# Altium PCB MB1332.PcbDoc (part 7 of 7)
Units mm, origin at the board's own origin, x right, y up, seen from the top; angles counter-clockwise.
Board outline 161 x 75 mm, 6 copper layers (Top Layer, Signal Layer 1, Signal Layer 2, Signal Layer 3, Signal Layer 4, Bottom Layer), stack 1.57 mm thick; 387 components, 358 nets, 1659 pads, 1180 vias.

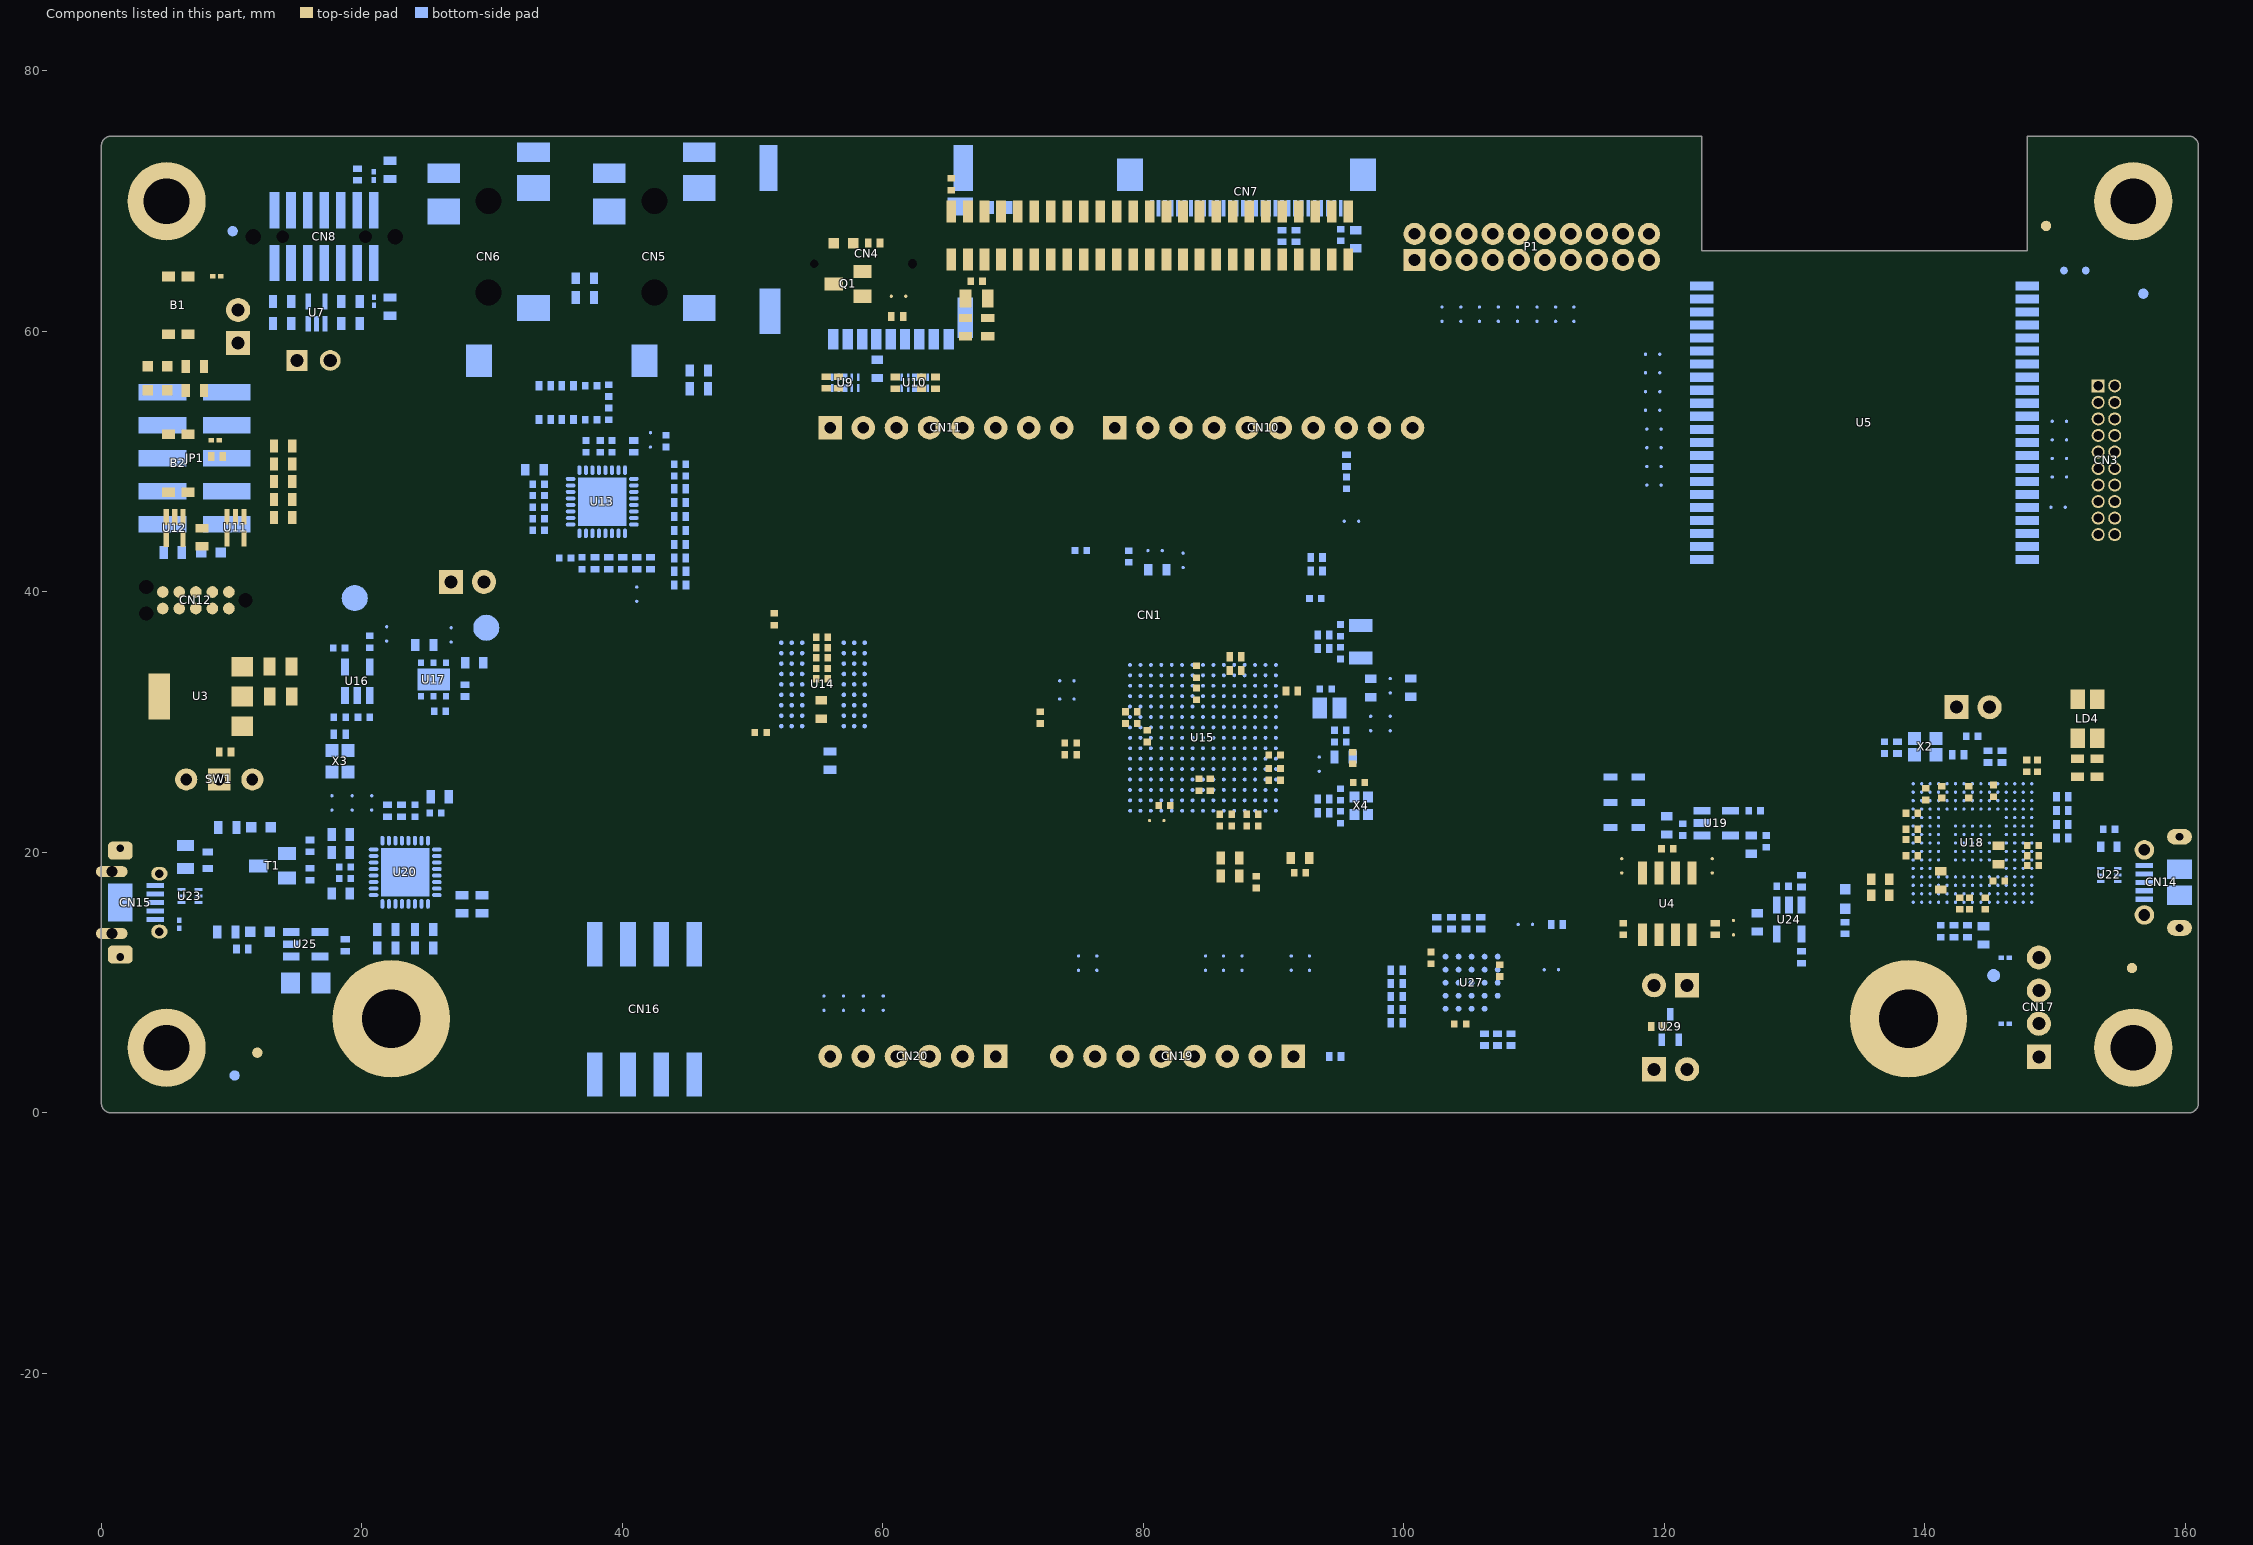
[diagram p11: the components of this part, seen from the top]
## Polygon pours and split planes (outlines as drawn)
GND on Bottom Layer "GND" (solid, remove dead copper, pour order 92): -6.45,72.925 -0.75,78.625 161.225,78.625 166.55,73.3 166.55,1.15 161.375,-4.025 0.525,-4.025 -6.45,2.95
GND on Bottom Layer "GND_L06_P010" (solid, remove dead copper, pour order 10): 96.6,28.248 96.5,28.148 95.3,28.148 95.225,28.223 95.225,29.648 95.35,29.773 96.525,29.773 96.6,29.698
VCAP on Bottom Layer "VCAP_L06_P014" (solid, remove dead copper, pour order 14): 98,29.598 98.1,29.498 98.1,27.123 97.95,26.973 97.075,26.973 96.8,27.248 96.8,29.498 96.9,29.598
VDD_LDO on Bottom Layer "VDD_LDO_L06_P016" (solid, remove dead copper, pour order 16): 99.5,29.598 99.6,29.498 99.6,27.123 99.45,26.973 98.4,26.973 98.3,27.073 98.3,29.498 98.4,29.598
1V8 on Bottom Layer "1V8_L06_P018" (solid, remove dead copper, pour order 18): 101.7,33.098 101.375,32.773 100.15,32.773 99.775,33.148 98.375,33.148 98.225,33.298 98.225,34.098 98.475,34.348 101.55,34.348 101.7,34.198
5V_VIN on Bottom Layer "5V_VIN" (solid, remove dead copper, pour order 90): 116.725,26.1 116.725,25.475 116.457,25.207 113.818,25.207 113.6,25.425 113.6,26.15 113.895,26.445 116.38,26.445
5V_USB_HS on Bottom Layer "5V_USB_HS" (solid, remove dead copper, pour order 88): 7.475,22.525 7.475,20.05 7.275,19.85 5.55,19.85 5.175,20.225 5.175,22.125 5.9,22.85 7.15,22.85
GND on Bottom Layer "GND_L06_P002" (solid, remove dead copper, pour order 2): 99.025,21.123 101.325,21.123 102.325,22.123 102.325,32.298 102.15,32.473 100.1,32.473 100,32.373 100,26.998 99.625,26.623 99.4,26.623 97.425,26.623 97.1,26.298 97.1,25.923 96.725,25.548 95.625,25.548 95.275,25.898 95.275,26.223 95.05,26.448 92.9,26.448 92.725,26.623 92.725,26.948 91.825,27.848 91.3,27.848 90.85,27.398 90.85,26.223 90.875,21.648 91.425,21.098 99,21.098
3V3_SMPS_IN on Bottom Layer "3V3_SMPS_IN_L06_P004" (solid, remove dead copper, pour order 4): 89.975,29.798 94.95,29.798 95.075,29.673 95.075,27.073 95,26.998 92.725,26.998 90.675,29.048 90.275,29.048 89.975,29.348
VDD_SMPS_OUT on Bottom Layer "VDD_SMPS_OUT_L06_P006" (solid, remove dead copper, pour order 6): 94.175,30.148 94.1,30.073 90.05,30.073 89.925,30.198 89.925,30.623 90.05,30.748 90.75,30.748 92.975,32.973 93.825,32.973 93.95,32.848 93.95,32.248 94.175,32.023
3V3_MCU on Bottom Layer "3V3_MCU_L06_P008" (solid, remove dead copper, pour order 8): 95.5,25.973 95.675,25.798 96.45,25.798 96.65,25.998 96.65,27.773 96.55,27.873 95.575,27.873 95.5,27.798
VDD_SMPS_IND_OUT on Bottom Layer "VDD_SMPS_IND_OUT_L06_P012" (solid, remove dead copper, pour order 12): 94.525,30.098 94.4,30.223 94.4,31.923 94.475,31.998 95,31.998 95.475,32.473 99.575,32.473 99.775,32.273 99.775,30.423 99.575,30.223 97.175,30.223 97.05,30.098
GND on Bottom Layer "GND_L06_P020" (solid, remove dead copper, pour order 20): 90.05,30.923 89.9,31.073 89.9,32.473 89.95,32.473 91.675,34.198 91.675,36.823 92.577,37.725 94.102,37.725 95.3,38.923 97.975,38.923 98.625,38.273 98.625,35.773 99.15,35.248 102.025,35.248 102.275,34.998 102.275,34.698 102.15,34.573 98.475,34.573 97.975,34.073 97.975,32.848 97.9,32.773 95,32.773 94.85,32.623 94.85,32.323 94.725,32.198 94.2,32.198 94.125,32.273 94.125,32.848 93.9,33.073 92.825,33.073 91.65,31.898 91.45,31.898 90.475,30.923
NetC93_2 on Bottom Layer "NetC93_2" (solid, remove dead copper, pour order 26): 26.12,36.67 27.392,36.67 27.65,36.412 27.65,35.4 27.275,35.025 26.1,35.025 25.975,34.9 25.975,34.264 25.725,34.014 24.211,34.014 23.925,34.3 23.925,34.85 24.175,35.1 24.632,35.1 24.9,35.368 24.9,36.4 25.175,36.675
NetC112_2 on Bottom Layer "NetC79_2" (solid, remove dead copper, pour order 36): 117.125,26.1 117.375,26.35 118.775,26.35 119.35,25.775 119.35,22.325 119.875,21.8 122.025,21.8 122.175,21.95 122.175,23.775 122.375,23.975 123.625,23.975 124.25,23.35 124.25,21.2 123.725,20.675 117.55,20.675 117.125,21.1
3V3 on Bottom Layer "3V3" (solid, remove dead copper, pour order 86): 27.7,39.05 28.175,38.575 28.175,36.75 27.9,36.475 25.425,36.475 24.7,37.2 24.7,38.7 25.05,39.05
3V3 on Signal Layer 3 "3V3" (solid, remove dead copper, pour order 56): -0.55,75.325 161.125,75.325 162.3,74.15 162.3,-0.4 160.725,-1.975 0.125,-1.975 -1.775,-0.075 -1.775,74.075
VCAP on Signal Layer 3 "VCAP_L04_P022" (solid, remove dead copper, pour order 22): 92.034,26.732 89.113,23.811 85.049,23.811 84.668,24.192 84.668,26.224 84.541,26.351 84.541,26.859 84.668,26.986 84.994,26.986 85.629,26.351 86.057,26.351 86.311,26.605 86.311,28.264 86.065,28.51 86.065,31.431 83.144,31.431 82.636,30.923 82.636,29.018 82.509,28.891 81.62,28.891 81.112,29.399 81.112,33.082 82.255,34.225 86.319,34.225 86.771,33.773 86.827,33.773 86.827,33.466 87.208,33.466 87.208,28.764 97.459,28.764 97.775,28.448 97.775,27.023 97.484,26.732
1V8 on Signal Layer 3 "1V8" (solid, remove dead copper, pour order 50): 40.3,42.525 36.075,42.525 33.6,45.025 26.85,45.025 23.1,41.275 23.1,39.7 23.1,32.625 25.325,30.4 25.325,22.9 24.275,21.85 23.725,21.85 21.725,23.85 21.725,31.725 20.925,32.525 20.925,38.5 20.925,41.85 30.975,51.9 44.4,51.9 45.003,51.297 45.003,47.228
5V on Signal Layer 3 "5V" (solid, remove dead copper, pour order 48): 72,33.075 70.925,32 66.075,32 60.2,37.875 48.125,37.875 41.575,31.325 28.175,31.325 27.725,31.775 27.725,33.875 29.25,35.4 41.425,35.4 47.85,41.825 62,41.825 68.825,35 71.3,35 72,34.3
3V3_MCU on Signal Layer 3 "3V3_MCU_L04_P024" (solid, remove dead copper, pour order 24): 72.75,34.144 71.444,35.45 69.05,35.45 62.165,42.335 47.639,42.335 41.214,35.91 28.815,35.91 28.15,36.575 28.15,41.439 28.961,42.25 30.45,42.25 30.95,41.75 30.95,38.7 31.65,38 39.025,38 46.05,45.025 72.071,45.025 96.075,45.025 97.112,46.062 98.313,46.062 98.475,45.9 98.475,44.7 97.075,43.3 94.55,43.3 94.325,43.025 94.325,39.625 93.27,38.57 81.139,38.57 78.064,35.495 78.064,25.462 78.826,24.7 82.509,24.7 83.017,25.208 83.017,26.07 82.89,26.197 82.89,30.796 83.271,31.177 85.303,31.177 85.321,31.159 85.829,31.159 86.065,30.923 86.065,29.399 85.811,29.145 85.811,28.383 86.065,28.129 86.065,26.732 85.937,26.605 85.544,26.605 85.376,26.773 85.376,27.041 85.176,27.24 84.541,27.24 84.414,27.113 84.414,23.938 84.922,23.43 89.24,23.43 92.158,26.348 96.349,26.348 99.65,26.348 100.05,25.948 100.05,13.948 99.372,13.27 69.682,13.27 69.301,13.651 69.301,29.626 72.75,33.075
VDD_LDO on Signal Layer 3 "VDD_LDO_L04_P028" (solid, remove dead copper, pour order 28): 78.445,25.589 78.953,25.081 82.382,25.081 82.756,25.462 82.756,27.374 80.604,29.526 80.604,33.336 81.874,34.606 86.573,34.606 87.35,33.829 87.35,30.469 87.102,30.467 87.102,29.94 87.97,29.071 97.677,29.071 98.1,28.648 98.1,27.098 98.593,26.605 99.757,26.605 100.05,26.898 100.05,37.448 99.336,38.162 81.239,38.162 78.445,35.368
5V_VIN on Signal Layer 3 "5V_VIN" (solid, remove dead copper, pour order 34): 7.65,27.913 8.962,29.225 13.4,29.225 13.8,29.625 13.8,31.142 13.367,31.575 -0.65,31.575 -1.425,30.75 -1.425,-1.375 -0.975,-1.825 94.95,-1.825 95.875,-0.9 95.875,3.375 95.425,3.825 94.675,3.825 92.9,2.05 20.3,2.05 10.325,12.025 8.75,12.025 7.65,13.125
3V3_STLK on Signal Layer 3 "3V3_STLK" (solid, remove dead copper, pour order 42): 151.175,14.625 151.175,3.225 150.375,2.425 147.35,2.425 146.525,3.25 146.525,14.525 145.75,15.25 135.575,15.25 129.75,21.075 127.25,21.075 126.7,21.625 126.7,25.125 135.925,34.35 152.025,34.35 152.631,33.744 152.631,27.456 150.675,25.5 150.675,22.763 151.007,22.431 154.281,22.431 154.8,22.95 155.8,22.95 156.45,22.3 156.45,19.9
5V on Signal Layer 3 "5V" (solid, remove dead copper, pour order 52): 110.225,70.05 110.85,69.425 110.85,67.625 114.4,64.075 120.767,64.075 121.475,63.367 121.475,20.775 119.825,19.125 117.925,19.125 116.9,20.15 116.9,50.773 104.878,62.9 73.05,62.9 67.375,57.225 62.825,57.225 61.3,58.75 31,58.75 25.125,52.875 4.225,52.875 3.55,52.2 3.625,52.125 3.625,45.275 3.125,44.775 1.345,44.775 0.5,45.62 0.5,55.233 1.192,55.925 24.15,55.925 29.25,61.025 61.875,61.025 70.9,70.05
GND on Signal Layer 2 "GND" (solid, remove dead copper, pour order 82): 1.8,79.7 -1.95,75.95 -1.95,-1.65 1.675,-5.275 162.475,-5.275 166.2,-1.55 166.2,73.375 159.75,79.825 1.925,79.825
5V_VIN on Signal Layer 2 "5V_VIN" (solid, remove dead copper, pour order 60): 115.575,26.35 115.575,25.725 96.2,6.35 96.2,3.95 95.125,2.875 94.4,2.875 93.925,3.35 93.925,4.625 94.95,5.65 94.95,7.475 114.15,26.675 115.25,26.675
5V on Signal Layer 2 "5V" (solid, remove dead copper, pour order 40): 146.2,34.125 133.2,34.125 125.25,26.175 125.25,21.325 123.1,19.175 119.125,19.175 118.275,20.025 118.275,21.4 119.05,22.175 121.1,22.175 122.325,23.4 122.325,27.7 131.25,36.625 145.9,36.625 146.425,37.225 146.425,43.625 147.95,45.15 149.675,45.15 150.075,44.75 150.075,44.025 149.675,43.625 149.15,43.625 148.4,42.875 148.4,36.175 153.25,31.325 153.25,22.275 152.35,21.375 150.775,21.375 150.2,21.95 150.2,30.125
5V on Signal Layer 2 "5V" (solid, remove dead copper, pour order 38): 11.655,31.225 12,30.881 12,30 12.5,29.5 13.275,29.5 13.9,30.125 13.9,30.9 14.225,31.225 25.075,31.225 27.575,33.725 29.125,33.725 29.55,33.3 29.55,30.1 26.15,26.7 5.1,26.7 4.675,26.275 4.675,21.975 10.25,16.4 10.25,13.275 11.3,12.175 13.475,12.175 19,17.7 19,19.075 19.3,19.375 20.35,19.375 20.6,19.125 20.6,16.175 18.587,14.187 18.587,12.838 15.325,9.575 9.966,9.575 6.8,12.775 6.8,13.95 5.825,14.925 5.825,18.6 2.3,22.125 2.3,35.775 0.525,37.55 0.525,55.019 1.406,55.9 2.725,55.9 3.3,55.325 3.3,45.25 5.638,42.913 5.675,32.25 6.7,31.225
5V_VIN on Signal Layer 2 "5V_VIN" (solid, remove dead copper, pour order 64): 6.414,48.314 5.425,47.325 5.425,44.85 8.35,41.925 8.35,35.525 12.15,31.725 12.17,31.725 12.17,30.105 12.6,29.675 13.175,29.675 13.675,30.175 13.675,33.7 10.575,36.8 10.575,46.4 11.15,46.975 12.533,46.975 13.039,47.481 13.039,47.969 12.694,48.314
VIN on Signal Layer 2 "VIN" (solid, remove dead copper, pour order 68): 14.05,35.375 13.6,34.925 12.646,34.925 12.25,35.321 12.25,36.425 13.575,37.75 38.15,37.75 48.85,27.05 48.85,25.575 48.525,25.25 47.075,25.25 36.95,35.375
5V_USB_CHARGER on Signal Layer 2 "5V_USB_CHARGER" (solid, remove dead copper, pour order 70): 155.975,22.175 153,22.175 152.05,21.225 150.4,21.225 150.025,21.6 150.025,25.275 148.9,26.4 134.35,26.4 129.75,21.8 129.75,17.35 126.35,13.95 126.35,12.075 128,10.425 135.1,10.425 138.65,13.975 153.125,13.975 156.35,17.2 156.35,21.8
GND on Top Layer "GND" (solid, remove dead copper, pour order 80): -1.45,78.475 161,78.475 164.75,74.725 164.75,-0.7 162.7,-2.75 1.125,-2.75 -3,1.375 -3,76.925
5V on Top Layer "5V" (solid, remove dead copper, pour order 44): 28.225,33.625 30.225,33.625 30.8,33.05 30.8,24.25 39.85,15.2 39.85,3.25 40.95,2.15 79.85,2.15 80.4,2.7 80.4,5.225 80.775,5.6 82.286,5.6 82.9,4.986 82.9,1.925 81.175,0.2 40,0.2 37.7,2.5 37.7,14.075 27.9,23.875 27.9,33.3
VIN on Top Layer "VIN" (solid, remove dead copper, pour order 66): 75.225,2.925 74.8,2.5 72.45,2.5 71.75,3.2 71.75,13 70.25,14.5 66.25,14.5 63.9,12.15 49.225,12.15 47.425,13.95 47.425,26.9 47.875,27.35 49.375,27.35 50.075,26.65 50.075,16.15 52.375,13.85 61.05,13.85 62.6,15.4 74.475,15.4 75.225,14.65
E5V on Top Layer "E5V" (solid, remove dead copper, pour order 58): 12.25,55.825 12.25,54 12.8,53.45 12.8,52.55 12.525,52.275 11.4,52.275 10.5,53.175 10.5,54.3 8.725,56.075 8.725,57.229 8.725,60.358 8.967,60.6 11.65,60.6 12.25,60 12.25,57.15
GND on Signal Layer 4 "GND" (solid, remove dead copper, pour order 78): -2.9,74.65 -2.9,0.825 -0.1,-1.975 0.025,-1.85 162.65,-1.85 165.45,0.95 165.45,72.875 161.125,77.2 -0.35,77.2
5V_USB_HS on Signal Layer 4 "5V_USB_HS" (solid, remove dead copper, pour order 72): -0.7,22.8 17.275,22.8 36.025,4.05 112.85,4.05 113.875,5.075 113.875,22 114.35,22.475 115.775,22.475 116.85,21.4 116.85,-1.025 115.85,-2.025 -1.125,-2.025 -2.725,-0.425 -1.3,1 -1.3,22.2
5V_USB_CHARGER on Signal Layer 4 "5V_USB_CHARGER" (solid, remove dead copper, pour order 74): 1.725,45.6 12.65,45.6 15.1,43.15 15.1,37.75 44.575,8.275 108.275,8.275 110.05,10.05 110.05,22.325 112.6,24.875 126.7,24.875 131.4,20.175 131.4,18.75 130.975,18.325 129.825,18.325 126.75,21.4 117,21.4 115.85,22.55 114.25,22.55 113.725,22.025 113.725,5.075 112.99,4.34 35.91,4.34 17.25,23 -0.55,23 -0.55,23.025 -1.125,23.6 -1.125,42.75
5V_USB_STLK on Signal Layer 4 "5V_USB_STLK" (solid, remove dead copper, pour order 76): -0.05,56.675 13.725,56.675 19.7,50.7 19.7,42.35 48.575,13.475 104.675,13.475 105.825,14.625 105.825,25.35 110.525,30.05 133.325,30.05 137.1,26.275 137.1,-2.125 0.65,-2.125 -1.475,0 -1.225,0.25 -1.225,55.5
GND on Signal Layer 1 "GND_L02_P000" (solid, remove dead copper, pour order 0): 161,75 161,0 0,0 0,75

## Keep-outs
Keep-Out Layer:
  region: 158.675,28.325 158.675,36.825 156.7,36.825 156.7,28.325

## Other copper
Top Layer:
  text "1" at 158.272,28.618 h2 r90
  text ".Layer_Name" at 39.428,-21.858 h3
  text ".GTL" at 81.123,-21.858 h3
Signal Layer 1:
  text "2" at 158.272,29.868 h2 r90
  text ".Layer_Name" at 39.428,-21.858 h3
  text ".G1" at 81.123,-21.858 h3
Signal Layer 2:
  text "3" at 158.272,31.368 h2 r90
  text ".Layer_Name" at 39.428,-21.858 h3
  text ".G2" at 81.123,-21.858 h3
Signal Layer 3:
  text "4" at 158.272,33.618 h2 r90
  text ".Layer_Name" at 39.46,-21.841 h3
  text ".G3" at 81.155,-21.841 h3
Signal Layer 4:
  text "5" at 158.272,35.118 h2 r90
  text ".Layer_Name" at 39.46,-21.841 h3
  text ".G4" at 81.155,-21.841 h3
Bottom Layer:
  text "6" at 158.272,36.618 h2 r90
  text ".GBL" at 69.92,-21.89 h3
  text ".Layer_Name" at 111.234,-21.89 h3

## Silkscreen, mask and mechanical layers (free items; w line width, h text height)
Top Overlay:
  lines w0.1: 6.6,23.5 12.775,23.5 ; 0.35,21.8 0.35,27.475 2.3,27.475 2.3,21.8 0.35,21.8 ; 159.025,22.15 159.025,30.375 160.65,30.375 160.65,22.15 159.025,22.15
  lines w0.254: 102.05,61.725 102.05,63.925 110.45,63.925 110.45,61.7 102.075,61.7 ; 156.2,27.325 156.225,27.35 ; 1.3,60 2.85,60 2.85,64.775 1.3,64.775 1.3,60 ; 1.55,48.15 1.55,51.8 3.1,51.8 3.1,48.15 1.55,48.15 ; 14.016,37.525 16.016,37.525 16.016,41.775 14.016,41.775 14.016,37.525
  text "RGB LCD" at 83,71.5 h2
  text "STMOD+" at 102.65,62.125 h2
  text "RESET" at 2.55,60.45 h1.3 r90
  text "USER" at 2.7,48.425 h1.3 r90
  text "TAG" at 15.591,37.775 h2 r90
  text "USB STLINK" at 160.3,22.475 h1.5 r90
  text "OTG HS" at 1.8,22.2 h1.5 r90
  text "0 / FLASH" at 11.25,21.825 h1.5
  text "1 / SYS  / MEM" at 4.25,20.725 h1.5
  text "J" at 6.075,13.675 h15
  text "MB1332C" at 4.275,10.375 h3
  text ".Layer_Name" at 39.428,-21.858 h3
  text ".GTO" at 81.123,-21.858 h3
Bottom Overlay:
  lines w0.01: 15.95,55.3 15.95,55.3
  lines w0.1: 15.05,56.1 16.225,54.925 ; 17.575,56.1 18.75,54.925 ; 0.9,21.375 0.9,27.05 2.8,27.05 2.8,21.375 0.9,21.375 ; 159.075,22.4 160.575,22.4 160.575,30.5 159.075,30.5 159.075,22.4
  lines w0.254: 71.9,71.075 71.925,71.1 ; 73.325,71.425 69.05,71.425 69.05,73.925 73.35,73.925 73.35,71.45 ; 84.475,65.875 76.075,65.875 76.075,68.125 84.475,68.125 84.475,66.225 ; 88.175,65.625 88.175,65.975 ; 127.675,30.4 122.8,30.4 122.8,32.65 127.7,32.65 127.7,30.425 ; 128.525,31.95 128.55,31.975 ; 0.35,45.175 2.475,45.175 2.475,55.25 0.35,55.25 0.35,45.175 ; 9.475,72.075 9.475,74.2 16.725,74.2 16.725,72.075 9.475,72.075 ; 28.75,2 28.75,4.375 35.5,4.375 35.5,4.125 35.5,2 28.75,2 ; 34.925,67.1 34.925,74.35 37.3,74.35 37.3,67.1 34.925,67.1 ; 47.625,65.475 49.875,65.475 49.875,74.25 47.625,74.25 47.625,65.475 ; 51.75,38.25 51.75,40.75 59,40.75 59,38.25 51.75,38.25 ; 92.35,13.825 92.35,16.25 101,16.25 101,13.825 92.35,13.825 ; 123.75,2.15 123.75,4.475 131,4.475 131,2.15 123.75,2.15
  text "DEBUG" at 16.25,72.475 h2
  text "µSD" at 72.775,72.225 h2
  text "AUDIO IN" at 35.65,67.95 h1.5 r270
  text "CAMERA" at 84.175,66.35 h2
  text "AUDIO OUT" at 48.2,66.2 h1.5 r270
  text "STLK" at 14.6,54.45 h1.3
  text "E5V" at 13.95,52.325 h1.3
  text "JTCK" at 18.475,51.975 h1.5 r315
  text "JTMS" at 21,51.95 h1.5 r315
  text "U5V" at 13.95,49.775 h1.3
  text "D7" at 74.1,49.65 h1.3 r315
  text "D0" at 56.375,49.6 h1.3 r315
  text "D4" at 66.375,49.575 h1.3 r315
  text "D6" at 71.5,49.575 h1.3 r315
  text "D5" at 68.975,49.55 h1.3 r315
  text "D9" at 80.575,49.55 h1.3 r315
  text "D1" at 58.875,49.5 h1.3 r315
  text "D3" at 63.9,49.5 h1.3 r315
  text "D8" at 77.95,49.5 h1.3 r315
  text "D2" at 61.35,49.475 h1.3 r315
  text "D10" at 83.6,49.225 h1.3 r315
  text "D11" at 86.125,49.225 h1.3 r315
  text "D14" at 99.275,49.125 h1.3 r315
  text "D12" at 88.475,49.1 h1.3 r315
  text "D15" at 101.9,49.075 h1.3 r315
  text "D13" at 91.225,49.025 h1.3 r315
  text "GND" at 93.575,48.9 h1.3 r315
  text "AVDD" at 98,48.45 h1.3 r315
  text "ARD" at 14.25,47.225 h1.3
  text "5V POWER" at 0.85,45.575 h2 r270
  text "CHGR" at 15.25,44.725 h1.3
  text "SDRAM" at 58.5,38.85 h2
  text "H" at 115.95,38.075 h20
  text "G" at 70.4,34.525 h12
  text "NRST" at 145.375,32.75 h1.5
  text "WIFI" at 126.975,30.925 h2
  text "C" at 115.1,30.8 h15
  text "F" at 70,25.65 h15
  text "J" at 44.65,22.75 h15
  text "USB STLINK" at 159.35,22.575 h1.5 r270
  text "OTG HS" at 1.325,21.725 h1.5 r270
  text "MB1332C" at 46.05,19.275 h3
  text "I" at 69.625,16.25 h15
  text "E" at 59.825,16.15 h15
  text "OCTOSPI" at 100.55,14.275 h2
  text "SWDIO" at 153.6,14.1 h1.3 r45
  text "GND" at 152.6,10.6 h1.3 r45
  text "SWCLK" at 153.625,8.875 h1.3 r45
  text "+3V3" at 152.625,5.425 h1.3 r45
  text "FDCAN" at 130.05,2.65 h2
  text "Ext I2C" at 35.225,2.45 h2
  text "A3" at 61.45,1.3 h1.3 r315
  text "A5" at 56.175,1.275 h1.3 r315
  text "A4" at 58.925,1.275 h1.3 r315
  text "A0" at 69.35,1.225 h1.3 r315
  text "A1" at 66.55,1.2 h1.3 r315
  text "A2" at 64.125,1.15 h1.3 r315
  text "5V" at 81.75,1.125 h1.3 r315
  text "3V3" at 84.5,0.875 h1.3 r315
  text "VIN" at 74.225,0.775 h1.3 r315
  text "GND" at 77.325,0.525 h1.3 r315
  text "GND" at 79.95,0.5 h1.3 r315
  text "NRST" at 87.9,0.1 h1.3 r315
  text "IOREF" at 90.975,0.1 h1.3 r315
  text ".GBO" at 69.92,-21.89 h3
  text ".Layer_Name" at 111.234,-21.89 h3
Top Paste:
  text ".Layer_Name" at 39.401,-21.848 h3
  text ".GTP" at 81.096,-21.848 h3
Bottom Paste:
  text ".GBP" at 69.811,-21.875 h3
  text ".Layer_Name" at 111.125,-21.875 h3
Top Solder:
  region: 158.675,28.325 158.675,36.825 156.7,36.825 156.7,28.325
  text ".Layer_Name" at 39.426,-21.923 h3
  text ".GTS" at 81.121,-21.923 h3
Bottom Solder:
  region: 158.675,28.325 158.675,36.825 156.675,36.825 156.675,28.325
  text ".GBS" at 69.836,-21.95 h3
  text ".Layer_Name" at 111.15,-21.95 h3
M1-Board Shape:
  lines w0.1: 0,0.75 ccw(c0.75,0.75) 0.75,0 160.25,0 ccw(c160.25,0.75) 161,0.75 161,74.25 ccw(c160.25,74.25) 160.25,75 158.076,75 147.861,75 147.861,66.2 122.861,66.2 122.861,75 119.525,75 40.625,75 0.75,75 ccw(c0.75,74.25) 0,74.25 0,0.75
M2-Board Dimensions:
  text ".Layer_Name" at 39.428,-21.858 h3
  text ".GM2" at 81.123,-21.858 h3
M14-Top Assembly:
  text ".Layer_Name" at 39.428,-21.858 h3
  text ".GM14" at 81.123,-21.858 h3
M15-Bottom Assembly:
  text ".GM15" at 69.92,-21.89 h3
  text ".Layer_Name" at 111.234,-21.89 h3
Drill Drawing:
  drawing of 454 lines, arcs and shapes, not listed
  text "IMPEDANCE TABLE : SDRAM, SD CARD, ULPI, CAMERA" at 187.175,131.866 h3
  text "PCB SPECIFICATIONS :" at 1.4,131.279 h3
  text "PCB : TYPE 3" at 149.812,131.047 h3
  text "A.   MATERIAL :" at 1.4,127.279 h3
  text "FR-4" at 39.9,127.279 h3
  text "TG-170" at 56.4,127.279 h3
  text "X  TG-150" at 74.65,127.279 h3
  text "TG-140" at 90.65,127.279 h3
  text "LAYER" at 191.425,126.866 h3
  text "TRACE" at 207.675,126.866 h3
  text "SPACING" at 218.175,126.866 h3
  text "IMPEDANCE" at 231.675,126.866 h3
  text "IMPEDANCE" at 248.675,126.866 h3
  text "TOL." at 267.425,126.866 h3
  text "ASPECT-RATIO, AXE Z :" at 149.812,125.547 h3
  text "(mm)" at 221.5,124.391 h2.5
  text "(mm)" at 209.675,124.341 h2.5
  text "B.   MATERIAL FAMILY :" at 1.4,124.279 h3
  text "N/A" at 39.9,124.279 h3
  text "(Single ended)" at 232.175,124.116 h2.5
  text "(Differential)" at 249.925,124.116 h2.5
  text "C.   SOLDERMASK COLOR :" at 1.4,121.279 h3
  text "GREEN" at 39.9,121.279 h3
  text "WHITE" at 56.4,121.279 h3
  text "X  BLUE" at 74.65,121.279 h3
  text "BLACK" at 90.65,121.279 h3
  text "+/- 15%" at 266.48,120.476 h3
  text "0.127" at 208.65,120.391 h3
  text "n/a" at 220.675,120.366 h3
  text "TOP/BOTTOM" at 187.655,120.351 h3
  text "55 ohm" at 235.03,120.301 h3
  text "n/a" at 254.58,120.251 h3
  text "6:1 to 8:1 / LEVEL \"B\"" at 149.83,118.799 h3
  text "D.   SILKSCREEN COLOR :" at 1.4,118.279 h3
  text "X  WHITE" at 39.9,118.279 h3
  text "YELLOW" at 56.4,118.279 h3
  text "BLACK" at 74.65,118.279 h3
  text "Blue ink PANTONE 2955" at 90.65,118.279 h3
  text "+/- 15%" at 266.485,116.961 h3
  text "0.102" at 208.655,116.876 h3
  text "n/a" at 220.68,116.851 h3
  text "LAYER 3" at 189.6,116.816 h3
  text "55 ohm" at 235.035,116.786 h3
  text "n/a" at 254.585,116.736 h3
  text "E.   SURFACE FINISH :" at 1.4,115.279 h3
  text "X  ENIG" at 39.9,115.279 h3
  text "IMMERSION SILVER" at 56.4,115.279 h3
  text "IMMERSION TIN" at 90.65,115.279 h3
  text "MINIMUM PARAMETERS" at 149.857,113.198 h3
  text "HASL" at 39.9,112.279 h3
  text "HASL (PB-FREE)" at 56.4,112.279 h3
  text "GOLDEN FINGER" at 90.65,112.279 h3
  text "IMPEDANCE TABLE   USB OTG HS, USB HS STLINK V3E" at 187.05,111.69 h3
  text "F.   IMPEDANCE CONTROL :" at 1.4,109.279 h3
  text "NO" at 39.9,109.279 h3
  text "X  YES  (SEE IMPEDANCE TABLE FOR DETAIL INFORMATION)" at 56.4,109.279 h3
  text "DEFAULT" at 149.857,107.698 h3
  text "LAYER" at 191.3,106.69 h3
  text "TRACE" at 207.55,106.69 h3
  text "SPACING" at 218.05,106.69 h3
  text "IMPEDANCE" at 231.55,106.69 h3
  text "IMPEDANCE" at 248.55,106.69 h3
  text "TOL." at 267.3,106.69 h3
  text "G.   THROUGH VIA :" at 1.4,106.279 h3
  text "PLUG THE VIAS WHICH ARE COVERED WITH SOLDERMASK ONE OR TWO SIDE." at 39.9,106.279 h3
  text "(mm)" at 221.375,104.215 h2.5
  text "(mm)" at 209.55,104.165 h2.5
  text "(Single ended)" at 232.05,103.94 h2.5
  text "(Differential)" at 249.8,103.94 h2.5
  text "PLUG MATERIAL :" at 39.9,103.279 h3
  text "X  SOLDERMASK" at 65.4,103.279 h3
  text "NON-CONDUCTIVE EPOXY." at 90.65,103.279 h3
  text "TRACKS : 0.1mm           / GAPS : 0.1mm" at 149.857,101.948 h3
  text "+/- 15%" at 266.355,100.3 h3
  text "H.   STACK-UP :" at 1.4,100.279 h3
  text "SEE LAYER STACK-UP SEQUENCE FOR OVERALL THICKNESS." at 39.9,100.279 h3
  text "0.155" at 208.525,100.215 h3
  text "0.226" at 220.55,100.19 h3
  text "TOP/BOTTOM" at 187.53,100.175 h3
  text "n/a" at 234.905,100.125 h3
  text "90 ohm" at 250.991,99.949 h3
  text "+/- 15%" at 266.36,96.785 h3
  text "0.130" at 208.53,96.7 h3
  text "0.251" at 220.555,96.675 h3
  text "LAYER 3" at 189.475,96.64 h3
  text "90 ohm" at 250.991,96.647 h3
  text "n/a" at 234.91,96.61 h3
  text "Layer" at 188.2,90.225 h2
  text "Name" at 196.574,90.225 h2
  text "Material" at 212.771,90.225 h2
  text "Thickness" at 227.325,90.225 h2
  text "Constant" at 239.28,90.225 h2
  text "Board Layer Stack" at 250.344,90.225 h2
  text "1" at 188.2,86.225 h2
  text "Top Overlay" at 196.574,86.225 h2
  text "2" at 188.2,82.225 h2
  text "Top Solder" at 196.574,82.225 h2
  text "Solder Resist" at 212.771,82.225 h2
  text "0,015mm" at 227.325,82.225 h2
  text "3,5" at 239.28,82.225 h2
  text "3" at 188.2,78.225 h2
  text "Top Layer" at 196.574,78.225 h2
  text "Copper" at 212.771,78.225 h2
  text "0,042mm" at 227.325,78.225 h2
  text "4" at 188.2,74.225 h2
  text "Dielectric 1" at 196.574,74.225 h2
  text "FR-4" at 212.771,74.225 h2
  text "0,099mm" at 227.325,74.225 h2
  text "4,2" at 239.28,74.225 h2
  text "5" at 188.2,70.225 h2
  text "Signal Layer 1" at 196.574,70.225 h2
  text "Copper" at 212.771,70.225 h2
  text "0,035mm" at 227.325,70.225 h2
  text "6" at 188.2,66.225 h2
  text "Dielectric 2" at 196.574,66.225 h2
  text "0,102mm" at 227.325,66.225 h2
  text "4,2" at 239.28,66.225 h2
  text "7" at 188.2,62.225 h2
  text "Signal Layer 2" at 196.574,62.225 h2
  text "Copper" at 212.771,62.225 h2
  text "0,035mm" at 227.325,62.225 h2
  text "8" at 188.2,58.225 h2
  text "Dielectric 3" at 196.574,58.225 h2
  text "0,946mm" at 227.325,58.225 h2
  text "4,2" at 239.28,58.225 h2
  text "9" at 188.2,54.225 h2
  text "Signal Layer 3" at 196.574,54.225 h2
  text "Copper" at 212.771,54.225 h2
  text "0,035mm" at 227.325,54.225 h2
  text "10" at 188.2,50.225 h2
  text "Dielectric 4" at 196.574,50.225 h2
  text "0,102mm" at 227.325,50.225 h2
  text "4,2" at 239.28,50.225 h2
  text "11" at 188.2,46.225 h2
  text "Signal Layer 4" at 196.574,46.225 h2
  text "Copper" at 212.771,46.225 h2
  text "0,035mm" at 227.325,46.225 h2
  text "12" at 188.2,42.225 h2
  text "Dielectric 5" at 196.574,42.225 h2
  text "0,099mm" at 227.325,42.225 h2
  text "4,2" at 239.28,42.225 h2
  text "13" at 188.2,38.225 h2
  text "Bottom Layer" at 196.574,38.225 h2
  text "Copper" at 212.771,38.225 h2
  text "0,042mm" at 227.325,38.225 h2
  text "14" at 188.2,34.225 h2
  text "Bottom Solder" at 196.574,34.225 h2
  text "Solder Resist" at 212.771,34.225 h2
  text "0,015mm" at 227.325,34.225 h2
  text "3,5" at 239.28,34.225 h2
  text "15" at 188.2,30.225 h2
  text "Bottom Overlay" at 196.574,30.225 h2
  text "Symbol" at 188.595,24.234 h2.4
  text "Count" at 197.994,24.234 h2.4
  text "Hole Size" at 208.625,24.234 h2.4
  text "Plated" at 227.952,24.234 h2.4
  text "Hole Type" at 236.203,24.234 h2.4
  text "Drill Layer Pair" at 248.214,24.234 h2.4
  text "Hole Length" at 270.995,24.234 h2.4
  text "Routed Path Length" at 289.294,24.234 h2.4
  text "1180" at 197.994,20.09 h2
  text "0,200mm (7,87mil)" at 208.625,20.09 h2
  text "PTH" at 227.952,20.09 h2
  text "Round" at 236.203,20.09 h2
  text "Top Layer - Bottom Layer" at 248.214,20.09 h2
  text "-" at 270.995,20.09 h2
  text "-" at 289.294,20.09 h2
  text "4" at 197.994,15.947 h2
  text "0,600mm (23,62mil)" at 208.625,15.947 h2
  text "PTH" at 227.952,15.947 h2
  text "Slot" at 236.203,15.947 h2
  text "Top Layer - Bottom Layer" at 248.214,15.947 h2
  text "1,300mm (51,18mil)" at 270.995,15.947 h2
  text "0,700mm (27,56mil)" at 289.294,15.947 h2
  text "T" at 187.807,15.694 h1.84
  text "2" at 197.994,11.804 h2
  text "0,650mm (25,59mil)" at 208.625,11.804 h2
  text "PTH" at 227.952,11.804 h2
  text "Slot" at 236.203,11.804 h2
  text "Top Layer - Bottom Layer" at 248.214,11.804 h2
  text "0,850mm (33,47mil)" at 270.995,11.804 h2
  text "0,200mm (7,88mil)" at 289.294,11.804 h2
  text "V" at 187.807,11.551 h1.84
  text "1" at 197.994,7.661 h2
  text "0,650mm (25,59mil)" at 208.625,7.661 h2
  text "NPTH" at 227.952,7.661 h2
  text "Round" at 236.203,7.661 h2
  text "Top Layer - Bottom Layer" at 248.214,7.661 h2
  text "-" at 270.995,7.661 h2
  text "-" at 289.294,7.661 h2
  text "R" at 187.807,7.407 h1.84
  text "1" at 197.994,3.518 h2
  text "0,700mm (27,56mil)" at 208.625,3.518 h2
  text "NPTH" at 227.952,3.518 h2
  text "Round" at 236.203,3.518 h2
  text "Top Layer - Bottom Layer" at 248.214,3.518 h2
  text "-" at 270.995,3.518 h2
  text "-" at 289.294,3.518 h2
  text "S" at 187.807,3.264 h1.84
  text "20" at 197.994,-0.625 h2
  text "0,700mm (27,56mil)" at 208.625,-0.625 h2
  text "PTH" at 227.952,-0.625 h2
  text "Round" at 236.203,-0.625 h2
  text "Top Layer - Bottom Layer" at 248.214,-0.625 h2
  text "-" at 270.995,-0.625 h2
  text "-" at 289.294,-0.625 h2
  text "Q" at 187.807,-0.879 h1.84
  text "2" at 197.994,-4.768 h2
  text "0,850mm (33,47mil)" at 208.625,-4.768 h2
  text "NPTH" at 227.952,-4.768 h2
  text "Slot" at 236.203,-4.768 h2
  text "Top Layer - Bottom Layer" at 248.214,-4.768 h2
  text "2,425mm (95,47mil)" at 270.995,-4.768 h2
  text "1,575mm (62,01mil)" at 289.294,-4.768 h2
  text "U" at 187.807,-5.022 h1.84
  text "57" at 197.994,-8.911 h2
  text "0,900mm (35,43mil)" at 208.625,-8.911 h2
  text "PTH" at 227.952,-8.911 h2
  text "Round" at 236.203,-8.911 h2
  text "Top Layer - Bottom Layer" at 248.214,-8.911 h2
  text "-" at 270.995,-8.911 h2
  text "-" at 289.294,-8.911 h2
  text "K" at 187.807,-9.165 h1.84
  text "2" at 197.994,-13.054 h2
  text "0,970mm (38,19mil)" at 208.625,-13.054 h2
  text "NPTH" at 227.952,-13.054 h2
  text "Round" at 236.203,-13.054 h2
  text "Top Layer - Bottom Layer" at 248.214,-13.054 h2
  text "-" at 270.995,-13.054 h2
  text "-" at 289.294,-13.054 h2
  text "16" at 197.994,-17.197 h2
  text "1,000mm (39,37mil)" at 208.625,-17.197 h2
  text "PTH" at 227.952,-17.197 h2
  text "Round" at 236.203,-17.197 h2
  text "Top Layer - Bottom Layer" at 248.214,-17.197 h2
  text "-" at 270.995,-17.197 h2
  text "-" at 289.294,-17.197 h2
  text "N" at 187.807,-17.451 h1.84
  text "3" at 197.994,-21.34 h2
  text "1,100mm (43,31mil)" at 208.625,-21.34 h2
  text "NPTH" at 227.952,-21.34 h2
  text "Round" at 236.203,-21.34 h2
  text "Top Layer - Bottom Layer" at 248.214,-21.34 h2
  text "-" at 270.995,-21.34 h2
  text "-" at 289.294,-21.34 h2
  text "O" at 187.807,-21.594 h1.84
  text ".Layer_Name" at 39.428,-21.858 h3
  text ".DRL" at 81.123,-21.858 h3
  text "2" at 197.994,-25.484 h2
  text "1,190mm (46,85mil)" at 208.625,-25.484 h2
  text "NPTH" at 227.952,-25.484 h2
  text "Round" at 236.203,-25.484 h2
  text "Top Layer - Bottom Layer" at 248.214,-25.484 h2
  text "-" at 270.995,-25.484 h2
  text "-" at 289.294,-25.484 h2
  text "4" at 197.994,-29.627 h2
  text "2,000mm (78,74mil)" at 208.625,-29.627 h2
  text "NPTH" at 227.952,-29.627 h2
  text "Round" at 236.203,-29.627 h2
  text "Top Layer - Bottom Layer" at 248.214,-29.627 h2
  text "-" at 270.995,-29.627 h2
  text "-" at 289.294,-29.627 h2
  text "M" at 187.807,-29.88 h1.84
  text "4" at 197.994,-33.77 h2
  text "3,500mm (137,80mil)" at 208.625,-33.77 h2
  text "PTH" at 227.952,-33.77 h2
  text "Round" at 236.203,-33.77 h2
  text "Top Layer - Bottom Layer" at 248.214,-33.77 h2
  text "-" at 270.995,-33.77 h2
  text "-" at 289.294,-33.77 h2
  text "P" at 187.807,-34.023 h1.84
  text "2" at 197.994,-37.913 h2
  text "4,500mm (177,17mil)" at 208.625,-37.913 h2
  text "PTH" at 227.952,-37.913 h2
  text "Round" at 236.203,-37.913 h2
  text "Top Layer - Bottom Layer" at 248.214,-37.913 h2
  text "-" at 270.995,-37.913 h2
  text "-" at 289.294,-37.913 h2
  text "1300 Total" at 197.994,-42.056 h2
  text "Slot definitions :" at 188.595,-44.956 h2
  text "Routed Path Length" at 202.248,-44.956 h2
  text "= Calculated from tool start centre position to tool end centre position." at 219.161,-44.956 h2
  text "Hole Length" at 202.248,-46.613 h2
  text "= Routed Path Length + Tool Size = Slot length as defined in the PCB layout" at 212.882,-46.613 h2
M20-Top Title Box:
  circle w0.254: c117.433,-28.579 r1.3
  region: 102.955,-29.672 92.199,-29.672 93.192,-27.179 101.05,-27.179 101.498,-26.42 103.707,-28.968
  region: 116.958,-21.342 101.431,-21.342 100.736,-23.118 99.526,-24.343 98.129,-22.483 98.129,-20.832 99.272,-19.435 100.708,-19.056 116.958,-19.056
  lines w0.254: 93.192,-27.179 101.984,-27.179 98.918,-23.641 cw(c100.721,-21.697) 100.962,-19.056 117.726,-19.056 116.964,-21.342 ; 96.506,-18.809 cw(c98.932,-19.78) 99.168,-17.177 ; 96.545,-18.777 92.199,-29.672 111.521,-29.672 ccw(c111.77,-26.937) 114.319,-27.957 ; 98.285,-22.711 103.707,-28.968 ; 98.539,-22.711 103.844,-28.833 ; 98.539,-22.457 103.844,-28.579 ; 98.637,-21.342 111.63,-21.342 ; 98.666,-22.33 103.971,-28.452 ; 98.793,-22.203 104.098,-28.325 ; 98.92,-22.076 104.225,-28.198 ; 99.047,-21.949 104.352,-28.071 ; 99.101,-19.997 104.406,-26.118 ; 99.17,-17.177 118.619,-17.177 114.32,-27.955 ; 99.174,-21.822 104.424,-27.881 ; 99.174,-21.568 104.479,-27.69 ; 99.174,-21.314 104.479,-27.436 ; 99.174,-20.425 104.479,-26.547 ; 99.301,-21.187 104.606,-27.309 ; 99.301,-20.806 104.606,-26.928 ; 100.672,-27.192 ccw(c100.777,-26.657) 101.075,-26.2 ; 101.759,-21.329 ccw(c101.733,-21.896) 101.403,-22.358 103.767,-25.087 cw(c101.964,-27.031) 102.696,-29.579 ; 108.04,-29.468 110.929,-21.088 ; 108.262,-29.418 111.132,-21.097 ; 108.389,-29.418 111.259,-21.097 ; 108.643,-29.418 111.513,-21.097 ; 108.897,-29.418 111.767,-21.097 ; 109.151,-29.418 112.021,-21.097 ; 109.405,-29.418 112.275,-21.097 ; 109.659,-29.418 112.529,-21.097 ; 109.913,-29.418 112.783,-21.097 ; 110.167,-29.418 113.037,-21.097 ; 110.376,-29.468 113.265,-21.088 ; 113.265,-21.342 116.958,-21.342 ; 116.29,-21.34 117.052,-19.054 ; 116.456,-21.342 117.218,-19.056 ; 116.71,-21.342 117.472,-19.056
  lines w0.3: 30.428,-28.558 90.428,-28.558 ; 30.428,-23.558 90.428,-23.558 ; 30.428,-18.558 90.428,-18.558 ; 70.428,-33.558 70.428,-18.558 ; 90.428,-33.558 90.428,-13.558 ; 108.04,-29.468 110.376,-29.468 ; 30.428,-33.558 120.428,-33.558 120.428,-13.558 30.428,-13.558 30.429,-33.558
  text "Project: '.Board_Name'" at 31.428,-16.774 h3
  text "Layer:" at 31.429,-21.858 h3
  text "Gerber:" at 71.417,-21.858 h3
  text "Variant: '.VariantName'" at 31.428,-26.858 h3
  text "'.Board_Reference'" at 71.544,-26.858 h3
  text "R" at 116.925,-29.341 h1.52
  text "Date: '.Board_Document_Date'" at 31.428,-31.858 h3
  text "Rev: '.Board_PCB_Revision'" at 71.487,-31.858 h3
M21-Bottom Title Box:
  circle w0.254: c33.611,-28.579 r1.3
  region: 34.086,-21.342 49.613,-21.342 50.307,-23.118 51.518,-24.343 52.915,-22.483 52.915,-20.832 51.772,-19.435 50.336,-19.056 34.086,-19.056
  region: 48.089,-29.672 58.845,-29.672 57.852,-27.179 49.994,-27.179 49.545,-26.42 47.337,-28.968
  lines w0.254: 33.572,-19.056 34.334,-21.342 ; 33.826,-19.056 34.588,-21.342 ; 33.992,-19.054 34.754,-21.34 ; 34.08,-21.342 33.318,-19.056 50.082,-19.056 cw(c50.322,-21.697) 52.126,-23.641 49.06,-27.179 57.852,-27.179 ; 34.086,-21.342 37.778,-21.342 ; 36.725,-27.957 ccw(c39.274,-26.937) 39.522,-29.672 58.845,-29.672 54.499,-18.777 ; 36.724,-27.955 32.424,-17.177 51.874,-17.177 ; 37.778,-21.088 40.668,-29.468 ; 38.007,-21.097 40.876,-29.418 ; 38.261,-21.097 41.13,-29.418 ; 38.515,-21.097 41.384,-29.418 ; 38.769,-21.097 41.638,-29.418 ; 39.023,-21.097 41.892,-29.418 ; 39.277,-21.097 42.146,-29.418 ; 39.414,-21.342 52.407,-21.342 ; 39.531,-21.097 42.4,-29.418 ; 39.785,-21.097 42.654,-29.418 ; 39.912,-21.097 42.781,-29.418 ; 40.114,-21.088 43.004,-29.468 ; 46.438,-27.309 51.743,-21.187 ; 46.438,-26.928 51.743,-20.806 ; 46.565,-27.69 51.87,-21.568 ; 46.565,-27.436 51.87,-21.314 ; 46.565,-26.547 51.87,-20.425 ; 46.62,-27.881 51.87,-21.822 ; 46.637,-26.118 51.942,-19.997 ; 46.692,-28.071 51.997,-21.949 ; 46.819,-28.198 52.124,-22.076 ; 46.946,-28.325 52.251,-22.203 ; 47.073,-28.452 52.378,-22.33 ; 47.2,-28.833 52.505,-22.711 ; 47.2,-28.579 52.505,-22.457 ; 47.337,-28.968 52.759,-22.711 ; 48.347,-29.579 cw(c49.08,-27.031) 47.276,-25.087 49.641,-22.358 ccw(c49.311,-21.896) 49.285,-21.329 ; 49.969,-26.2 ccw(c50.266,-26.657) 50.371,-27.192 ; 51.875,-17.177 cw(c52.112,-19.78) 54.538,-18.809
  lines w0.3: 40.668,-29.468 43.004,-29.468 ; 60.428,-33.558 60.428,-13.558 ; 60.428,-28.558 120.428,-28.558 ; 60.428,-23.558 120.428,-23.558 ; 60.428,-18.558 120.428,-18.558 ; 80.428,-33.558 80.428,-18.558 ; 30.428,-33.558 30.428,-13.558 120.428,-13.558 120.428,-33.558 30.428,-33.558
  text "Project: '.Board_Name'" at 119.234,-16.774 h3
  text "Gerber:" at 79.245,-21.858 h3
  text "Layer:" at 119.234,-21.858 h3
  text "'.Board_Reference'" at 79.245,-26.858 h3
  text "Variant: '.VariantName'" at 119.234,-26.858 h3
  text "R" at 34.119,-29.341 h1.52
  text "Rev: '.Board_PCB_Revision'" at 79.302,-31.858 h3
  text "Date: '.Board_Document_Date'" at 119.234,-31.858 h3

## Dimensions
0,74.25 to 161,74.25 on M2-Board Dimensions
0.75,0 to 0.75,75 on M2-Board Dimensions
